VERSION 5.7 ;
  NOWIREEXTENSIONATPIN ON ;
  DIVIDERCHAR "/" ;
  BUSBITCHARS "[]" ;
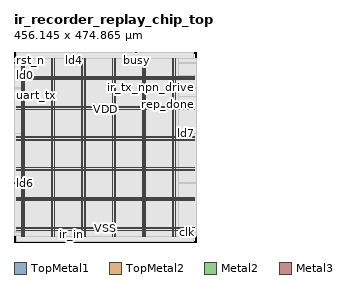
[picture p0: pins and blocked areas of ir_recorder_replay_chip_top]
MACRO ir_recorder_replay_chip_top
  CLASS BLOCK ;
  FOREIGN ir_recorder_replay_chip_top ;
  ORIGIN 0.000 0.000 ;
  SIZE 456.145 BY 474.865 ;
  PIN VDD
    DIRECTION INOUT ;
    USE POWER ;
    PORT
      LAYER TopMetal1 ;
        RECT 18.260 14.900 20.460 458.010 ;
    END
    PORT
      LAYER TopMetal1 ;
        RECT 93.860 14.900 96.060 458.010 ;
    END
    PORT
      LAYER TopMetal1 ;
        RECT 169.460 14.900 171.660 458.010 ;
    END
    PORT
      LAYER TopMetal1 ;
        RECT 245.060 14.900 247.260 458.010 ;
    END
    PORT
      LAYER TopMetal1 ;
        RECT 320.660 14.900 322.860 458.010 ;
    END
    PORT
      LAYER TopMetal1 ;
        RECT 396.260 14.900 398.460 458.010 ;
    END
    PORT
      LAYER TopMetal2 ;
        RECT 5.760 27.620 450.240 29.820 ;
    END
    PORT
      LAYER TopMetal2 ;
        RECT 5.760 103.220 450.240 105.420 ;
    END
    PORT
      LAYER TopMetal2 ;
        RECT 5.760 178.820 450.240 181.020 ;
    END
    PORT
      LAYER TopMetal2 ;
        RECT 5.760 254.420 450.240 256.620 ;
    END
    PORT
      LAYER TopMetal2 ;
        RECT 5.760 330.020 450.240 332.220 ;
    END
    PORT
      LAYER TopMetal2 ;
        RECT 5.760 405.620 450.240 407.820 ;
    END
  END VDD
  PIN VSS
    DIRECTION INOUT ;
    USE GROUND ;
    PORT
      LAYER TopMetal1 ;
        RECT 24.460 14.490 26.660 457.600 ;
    END
    PORT
      LAYER TopMetal1 ;
        RECT 100.060 14.490 102.260 457.600 ;
    END
    PORT
      LAYER TopMetal1 ;
        RECT 175.660 14.490 177.860 457.600 ;
    END
    PORT
      LAYER TopMetal1 ;
        RECT 251.260 14.490 253.460 457.600 ;
    END
    PORT
      LAYER TopMetal1 ;
        RECT 326.860 14.490 329.060 457.600 ;
    END
    PORT
      LAYER TopMetal1 ;
        RECT 402.460 14.490 404.660 457.600 ;
    END
    PORT
      LAYER TopMetal2 ;
        RECT 5.760 33.820 450.240 36.020 ;
    END
    PORT
      LAYER TopMetal2 ;
        RECT 5.760 109.420 450.240 111.620 ;
    END
    PORT
      LAYER TopMetal2 ;
        RECT 5.760 185.020 450.240 187.220 ;
    END
    PORT
      LAYER TopMetal2 ;
        RECT 5.760 260.620 450.240 262.820 ;
    END
    PORT
      LAYER TopMetal2 ;
        RECT 5.760 336.220 450.240 338.420 ;
    END
    PORT
      LAYER TopMetal2 ;
        RECT 5.760 411.820 450.240 414.020 ;
    END
  END VSS
  PIN busy
    DIRECTION OUTPUT ;
    USE SIGNAL ;
    ANTENNADIFFAREA 0.708600 ;
    PORT
      LAYER Metal2 ;
        RECT 308.440 474.465 308.840 474.865 ;
    END
  END busy
  PIN clk
    DIRECTION INPUT ;
    USE SIGNAL ;
    ANTENNAGATEAREA 1.450800 ;
    PORT
      LAYER Metal3 ;
        RECT 455.745 24.580 456.145 24.980 ;
    END
  END clk
  PIN error
    DIRECTION OUTPUT ;
    USE SIGNAL ;
    ANTENNADIFFAREA 0.708600 ;
    PORT
      LAYER Metal2 ;
        RECT 307.480 474.465 307.880 474.865 ;
    END
  END error
  PIN ir_in
    DIRECTION INPUT ;
    USE SIGNAL ;
    ANTENNAGATEAREA 0.180700 ;
    PORT
      LAYER Metal2 ;
        RECT 143.320 0.000 143.720 0.400 ;
    END
  END ir_in
  PIN ir_tx_npn_drive
    DIRECTION OUTPUT ;
    USE SIGNAL ;
    ANTENNADIFFAREA 0.708600 ;
    PORT
      LAYER Metal3 ;
        RECT 455.745 384.940 456.145 385.340 ;
    END
  END ir_tx_npn_drive
  PIN ld0
    DIRECTION OUTPUT ;
    USE SIGNAL ;
    ANTENNADIFFAREA 0.708600 ;
    PORT
      LAYER Metal3 ;
        RECT 0.000 415.180 0.400 415.580 ;
    END
  END ld0
  PIN ld1
    DIRECTION OUTPUT ;
    USE SIGNAL ;
    ANTENNADIFFAREA 0.708600 ;
    PORT
      LAYER Metal2 ;
        RECT 305.560 474.465 305.960 474.865 ;
    END
  END ld1
  PIN ld2
    DIRECTION OUTPUT ;
    USE SIGNAL ;
    ANTENNADIFFAREA 0.708600 ;
    PORT
      LAYER Metal2 ;
        RECT 355.480 474.465 355.880 474.865 ;
    END
  END ld2
  PIN ld3
    DIRECTION OUTPUT ;
    USE SIGNAL ;
    ANTENNADIFFAREA 0.708600 ;
    PORT
      LAYER Metal2 ;
        RECT 328.600 474.465 329.000 474.865 ;
    END
  END ld3
  PIN ld4
    DIRECTION OUTPUT ;
    USE SIGNAL ;
    ANTENNADIFFAREA 0.708600 ;
    PORT
      LAYER Metal2 ;
        RECT 149.080 474.465 149.480 474.865 ;
    END
  END ld4
  PIN ld5
    DIRECTION OUTPUT ;
    USE SIGNAL ;
    ANTENNADIFFAREA 0.708600 ;
    PORT
      LAYER Metal2 ;
        RECT 326.680 474.465 327.080 474.865 ;
    END
  END ld5
  PIN ld6
    DIRECTION OUTPUT ;
    USE SIGNAL ;
    ANTENNADIFFAREA 0.708600 ;
    PORT
      LAYER Metal3 ;
        RECT 0.000 147.220 0.400 147.620 ;
    END
  END ld6
  PIN ld7
    DIRECTION OUTPUT ;
    USE SIGNAL ;
    ANTENNADIFFAREA 0.708600 ;
    PORT
      LAYER Metal3 ;
        RECT 455.745 271.540 456.145 271.940 ;
    END
  END ld7
  PIN rec_done
    DIRECTION OUTPUT ;
    USE SIGNAL ;
    ANTENNADIFFAREA 0.708600 ;
    PORT
      LAYER Metal2 ;
        RECT 304.600 474.465 305.000 474.865 ;
    END
  END rec_done
  PIN record_req
    DIRECTION INPUT ;
    USE SIGNAL ;
    ANTENNAGATEAREA 0.180700 ;
    PORT
      LAYER Metal2 ;
        RECT 303.640 474.465 304.040 474.865 ;
    END
  END record_req
  PIN rep_done
    DIRECTION OUTPUT ;
    USE SIGNAL ;
    ANTENNADIFFAREA 0.708600 ;
    PORT
      LAYER Metal3 ;
        RECT 455.745 363.100 456.145 363.500 ;
    END
  END rep_done
  PIN replay_req
    DIRECTION INPUT ;
    USE SIGNAL ;
    ANTENNAGATEAREA 0.180700 ;
    PORT
      LAYER Metal2 ;
        RECT 323.800 474.465 324.200 474.865 ;
    END
  END replay_req
  PIN rst_n
    DIRECTION INPUT ;
    USE SIGNAL ;
    ANTENNAGATEAREA 0.180700 ;
    PORT
      LAYER Metal3 ;
        RECT 0.000 447.100 0.400 447.500 ;
    END
  END rst_n
  PIN slot_sel[0]
    DIRECTION INPUT ;
    USE SIGNAL ;
    ANTENNAGATEAREA 0.180700 ;
    PORT
      LAYER Metal2 ;
        RECT 277.720 474.465 278.120 474.865 ;
    END
  END slot_sel[0]
  PIN slot_sel[1]
    DIRECTION INPUT ;
    USE SIGNAL ;
    ANTENNAGATEAREA 0.180700 ;
    PORT
      LAYER Metal2 ;
        RECT 276.760 474.465 277.160 474.865 ;
    END
  END slot_sel[1]
  PIN slot_sel[2]
    DIRECTION INPUT ;
    USE SIGNAL ;
    ANTENNAGATEAREA 0.180700 ;
    PORT
      LAYER Metal2 ;
        RECT 293.080 474.465 293.480 474.865 ;
    END
  END slot_sel[2]
  PIN uart_tx
    DIRECTION OUTPUT ;
    USE SIGNAL ;
    ANTENNADIFFAREA 0.708600 ;
    PORT
      LAYER Metal3 ;
        RECT 0.000 386.620 0.400 387.020 ;
    END
  END uart_tx
  OBS
      LAYER GatPoly ;
        RECT 5.760 14.970 450.240 457.530 ;
      LAYER Metal1 ;
        RECT 5.760 14.900 450.240 457.600 ;
      LAYER Metal2 ;
        RECT 6.135 474.255 148.870 474.700 ;
        RECT 149.690 474.255 276.550 474.700 ;
        RECT 277.370 474.255 277.510 474.700 ;
        RECT 278.330 474.255 292.870 474.700 ;
        RECT 293.690 474.255 303.430 474.700 ;
        RECT 304.250 474.255 304.390 474.700 ;
        RECT 305.210 474.255 305.350 474.700 ;
        RECT 306.170 474.255 307.270 474.700 ;
        RECT 308.090 474.255 308.230 474.700 ;
        RECT 309.050 474.255 323.590 474.700 ;
        RECT 324.410 474.255 326.470 474.700 ;
        RECT 327.290 474.255 328.390 474.700 ;
        RECT 329.210 474.255 355.270 474.700 ;
        RECT 356.090 474.255 449.865 474.700 ;
        RECT 6.135 0.610 449.865 474.255 ;
        RECT 6.135 0.400 143.110 0.610 ;
        RECT 143.930 0.400 449.865 0.610 ;
      LAYER Metal3 ;
        RECT 0.400 447.710 455.745 457.480 ;
        RECT 0.610 446.890 455.745 447.710 ;
        RECT 0.400 415.790 455.745 446.890 ;
        RECT 0.610 414.970 455.745 415.790 ;
        RECT 0.400 387.230 455.745 414.970 ;
        RECT 0.610 386.410 455.745 387.230 ;
        RECT 0.400 385.550 455.745 386.410 ;
        RECT 0.400 384.730 455.535 385.550 ;
        RECT 0.400 363.710 455.745 384.730 ;
        RECT 0.400 362.890 455.535 363.710 ;
        RECT 0.400 272.150 455.745 362.890 ;
        RECT 0.400 271.330 455.535 272.150 ;
        RECT 0.400 147.830 455.745 271.330 ;
        RECT 0.610 147.010 455.745 147.830 ;
        RECT 0.400 25.190 455.745 147.010 ;
        RECT 0.400 24.370 455.535 25.190 ;
        RECT 0.400 15.020 455.745 24.370 ;
      LAYER Metal4 ;
        RECT 18.440 14.975 411.460 457.525 ;
      LAYER Metal5 ;
        RECT 18.395 14.810 404.525 457.690 ;
  END
END ir_recorder_replay_chip_top
END LIBRARY

